VERSION 5.7 ;
  NOWIREEXTENSIONATPIN ON ;
  DIVIDERCHAR "/" ;
  BUSBITCHARS "[]" ;
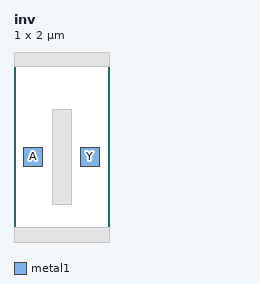
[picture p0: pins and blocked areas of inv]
MACRO inv
  CLASS BLOCK ;
  FOREIGN inv ;
  ORIGIN 0.00 0.00 ;
  SIZE 1.00 BY 2.00 ;
  PIN A
    DIRECTION INPUT ;
    USE SIGNAL ;
    PORT
      LAYER metal1 ;
        RECT 0.10 0.80 0.30 1.00 ;
    END
  END A
  PIN Y
    DIRECTION OUTPUT ;
    USE SIGNAL ;
    PORT
      LAYER metal1 ;
        RECT 0.70 0.80 0.90 1.00 ;
    END
  END Y
  OBS
      LAYER metal1 ;
        RECT 0.00 1.85 1.00 2.00 ;
        RECT 0.40 0.40 0.60 1.40 ;
        RECT 0.00 0.00 1.00 0.15 ;
  END
END inv
END LIBRARY

